VERSION 5.8 ;
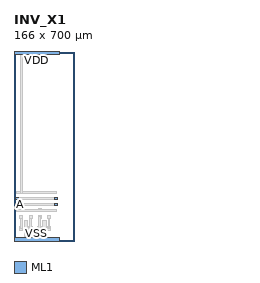
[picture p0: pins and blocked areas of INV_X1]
MACRO INV_X1
  CLASS CORE ;
  ORIGIN 0 0 ;
  SIZE 166 BY 700 ;
  SITE ICPS2023_5_ROW700 ;
  PIN A
    DIRECTION INPUT ;
    USE SIGNAL ;
    PORT
      LAYER ML1 ;
        RECT 5 130 15 140 ;
        RECT 151 130 161 140 ;
    END
  END A
  PIN Y
    DIRECTION OUTPUT ;
    USE SIGNAL ;
    PORT
      LAYER ML1 ;
        RECT 5 152 15 162 ;
        RECT 151 152 161 162 ;
    END
  END Y
  PIN VDD
    DIRECTION INOUT ;
    USE POWER ;
    PORT
      LAYER ML1 ;
        RECT 0 688 166 700 ;
    END
  END VDD
  PIN VSS
    DIRECTION INOUT ;
    USE GROUND ;
    PORT
      LAYER ML1 ;
        RECT 0 0 166 12 ;
    END
  END VSS
  OBS
    LAYER ML1 ;
      RECT 20 39.5 33 52.5 ;
      RECT 55 39.5 68 52.5 ;
      RECT 37.5 16 50.5 29 ;
      RECT 37.5 63 50.5 76 ;
      RECT 37 16 51 76 ;
      RECT 23.5 46 29.5 89 ;
      RECT 21.5 84 31.5 94 ;
      RECT 21.5 174 31.5 184 ;
      RECT 58.5 46 64.5 89 ;
      RECT 56.5 84 66.5 94 ;
      RECT 56.5 152 66.5 162 ;
      RECT 39 130 49 140 ;
      RECT 88 39.5 101 52.5 ;
      RECT 123 39.5 136 52.5 ;
      RECT 105.5 16 118.5 29 ;
      RECT 105.5 63 118.5 76 ;
      RECT 105 16 119 76 ;
      RECT 91.5 46 97.5 89 ;
      RECT 89.5 84 99.5 94 ;
      RECT 89.5 108 99.5 118 ;
      RECT 126.5 46 132.5 89 ;
      RECT 124.5 84 134.5 94 ;
      RECT 124.5 152 134.5 162 ;
      RECT 107 130 117 140 ;
      RECT 10 110 156 116 ;
      RECT 10 132 156 138 ;
      RECT 10 154 156 160 ;
      RECT 10 176 156 182 ;
      RECT 91.5 3 97.5 92 ;
      RECT 23.5 176 29.5 697 ;
  END
END INV_X1
